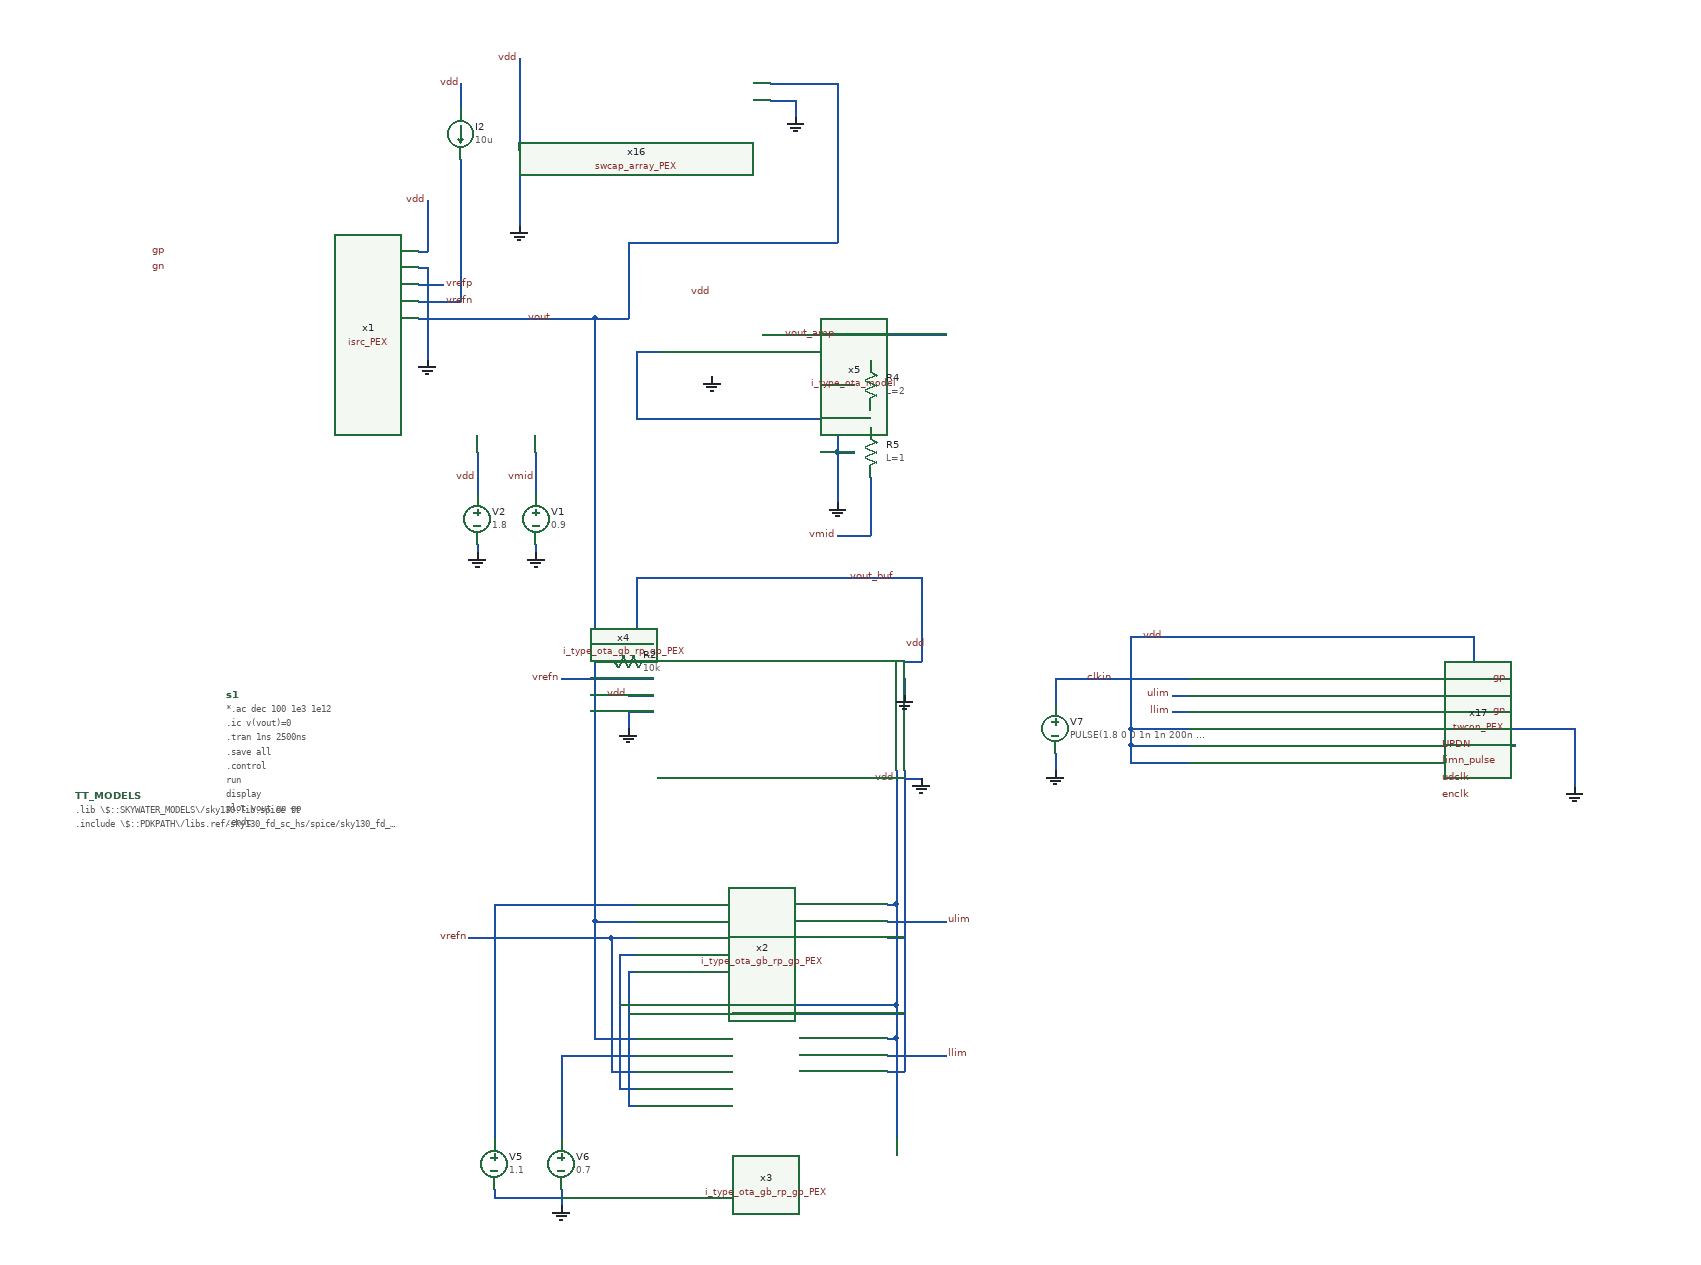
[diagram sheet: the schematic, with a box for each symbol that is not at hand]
v {xschem version=3.1.0 file_version=1.2
}
G {}
K {}
V {}
S {}
E {}
N 440 -10 440 0 {
lab=GND}
N 510 90 510 280 {
lab=vout}
N 470 660 470 700 {
lab=#net1}
N 390 550 390 700 {
lab=#net2}
N 470 760 470 780 {
lab=GND}
N 390 760 390 770 {
lab=GND}
N 390 770 470 770 {
lab=GND}
N 1060 240 1060 260 {
lab=GND}
N 390 -280 460 -280 {
lab=vout}
N 510 -280 510 90 {
lab=vout}
N 460 -280 510 -280 {
lab=vout}
N 440 -120 440 -70 {
lab=vmid}
N 840 -170 840 -150 {
lab=#net3}
N 800 -200 820 -200 {
lab=GND}
N 800 -200 800 -120 {
lab=GND}
N 800 -120 820 -120 {
lab=GND}
N 800 -120 800 -60 {
lab=GND}
N 840 -260 840 -230 {
lab=vout_amp}
N 710 -260 840 -260 {
lab=vout_amp}
N 560 -240 590 -240 {
lab=#net3}
N 560 -160 840 -160 {
lab=#net3}
N 560 -240 560 -160 {
lab=#net3}
N 800 -20 840 -20 {
lab=vmid}
N 840 -90 840 -20 {
lab=vmid}
N 840 -260 930 -260 {
lab=vout_amp}
N 1060 150 1060 180 {
lab=clkin}
N 1060 150 1100 150 {
lab=clkin}
N 750 -540 750 -520 {
lab=GND}
N 720 -540 750 -540 {
lab=GND}
N 720 -560 800 -560 {
lab=vout}
N 800 -560 800 -370 {
lab=vout}
N 550 -370 800 -370 {
lab=vout}
N 550 -370 550 -280 {
lab=vout}
N 420 -590 420 -560 {
lab=vdd}
N 1100 150 1220 150 {
lab=clkin}
N 1200 170 1220 170 {
lab=ulim}
N 1200 190 1220 190 {
lab=llim}
N 1190 100 1560 100 {
lab=vdd}
N 1560 100 1560 160 {
lab=vdd}
N 1560 160 1560 170 {
lab=vdd}
N 1520 170 1560 170 {
lab=vdd}
N 1150 100 1190 100 {
lab=vdd}
N 1150 100 1150 210 {
lab=vdd}
N 1150 210 1220 210 {
lab=vdd}
N 1150 230 1220 230 {
lab=vdd}
N 1150 250 1220 250 {
lab=vdd}
N 1150 230 1150 250 {
lab=vdd}
N 1520 150 1580 150 {
lab=gp}
N 1520 210 1560 210 {
lab=GND}
N 1680 210 1680 280 {
lab=GND}
N 1520 190 1580 190 {
lab=gn}
N 1560 210 1680 210 {
lab=GND}
N 1520 230 1610 230 {
lab=UPDN}
N 1150 210 1150 230 {
lab=vdd}
N 300 -360 310 -360 {
lab=vdd}
N 310 -420 310 -360 {
lab=vdd}
N 310 -340 310 -230 {
lab=GND}
N 300 -340 310 -340 {
lab=GND}
N 300 -280 390 -280 {
lab=vout}
N 350 -560 350 -530 {
lab=vdd}
N 370 -120 370 -70 {
lab=vdd}
N 370 -10 370 0 {
lab=GND}
N 300 -320 330 -320 {
lab=vrefp}
N 300 -300 330 -300 {
lab=vrefn}
N 350 -470 350 -300 {
lab=vrefn}
N 330 -300 350 -300 {
lab=vrefn}
N 860 420 870 420 {
lab=vdd}
N 860 440 930 440 {
lab=ulim}
N 860 460 880 460 {
lab=GND}
N 870 260 870 420 {
lab=vdd}
N 870 420 870 540 {
lab=vdd}
N 880 260 880 540 {
lab=GND}
N 880 270 900 270 {
lab=GND}
N 860 580 870 580 {
lab=vdd}
N 860 600 930 600 {
lab=llim}
N 860 620 880 620 {
lab=GND}
N 870 580 870 700 {
lab=vdd}
N 870 540 870 580 {
lab=vdd}
N 880 540 880 620 {
lab=GND}
N 390 440 390 550 {
lab=#net2}
N 390 420 390 440 {
lab=#net2}
N 390 420 560 420 {
lab=#net2}
N 470 600 470 660 {
lab=#net1}
N 470 600 560 600 {
lab=#net1}
N 540 480 560 480 {
lab=vdd}
N 540 480 540 640 {
lab=vdd}
N 540 640 560 640 {
lab=vdd}
N 550 660 560 660 {
lab=GND}
N 550 500 550 660 {
lab=GND}
N 550 500 560 500 {
lab=GND}
N 540 540 870 540 {
lab=vdd}
N 550 550 880 550 {
lab=GND}
N 530 460 560 460 {
lab=vrefn}
N 530 460 530 620 {
lab=vrefn}
N 530 620 560 620 {
lab=vrefn}
N 360 460 530 460 {
lab=vrefn}
N 510 440 560 440 {
lab=vout}
N 510 440 510 580 {
lab=vout}
N 510 580 560 580 {
lab=vout}
N 510 280 510 440 {
lab=vout}
N 510 -280 550 -280 {
lab=vout}
N 420 -560 420 -480 {
lab=vdd}
N 420 -460 420 -390 {
lab=GND}
N 560 110 580 110 {
lab=vout_buf}
N 560 30 560 110 {
lab=vout_buf}
N 560 30 900 30 {
lab=vout_buf}
N 900 30 900 130 {
lab=vout_buf}
N 890 130 900 130 {
lab=vout_buf}
N 880 130 890 130 {
lab=vout_buf}
N 880 150 880 170 {
lab=GND}
N 550 190 550 210 {
lab=GND}
N 470 150 490 150 {
lab=vrefn}
N 490 150 580 150 {
lab=vrefn}
N 510 130 520 130 {
lab=vout}
N 550 170 580 170 {
lab=vdd}
N 550 190 580 190 {
lab=GND}
C {devices/gnd.sym} 440 0 0 0 {name=l2 lab=GND}
C {devices/vsource.sym} 440 -40 0 0 {name=V1 value=0.9}
C {devices/vsource.sym} 370 -40 0 0 {name=V2 value=1.8}
C {devices/lab_wire.sym} 370 -90 0 0 {name=p1 sig_type=std_logic lab=vdd}
C {devices/lab_wire.sym} 460 -280 0 0 {name=p2 sig_type=std_logic lab=vout}
C {devices/code.sym} -110 290 0 0 {name=TT_MODELS only_toplevel=false
format="tcleval(@value )" value=".lib \\\\$::SKYWATER_MODELS\\\\/sky130.lib.spice tt
.include \\\\$::PDKPATH\\\\/libs.ref/sky130_fd_sc_hs/spice/sky130_fd_sc_hs.spice"}
C {devices/code_shown.sym} 70 170 0 0 {name=s1
only_toplevel=false
value="
*.ac dec 100 1e3 1e12
.ic v(vout)=0
.tran 1ns 2500ns
.save all
.control
run
display
plot vout gn gp
.endc
"}
C {devices/lab_wire.sym} 870 270 0 0 {name=p7 sig_type=std_logic lab=vdd}
C {devices/lab_wire.sym} 930 440 0 1 {name=p8 sig_type=std_logic lab=ulim}
C {devices/vsource.sym} 390 730 0 0 {name=V5 value="1.1"}
C {devices/vsource.sym} 470 730 0 0 {name=V6 value="0.7"}
C {devices/gnd.sym} 470 780 0 0 {name=l7 lab=GND}
C {devices/vsource.sym} 1060 210 0 0 {name=V7 value="PULSE(1.8 0 0 1n 1n 200n 400n)"}
C {devices/gnd.sym} 1060 260 0 0 {name=l8 lab=GND}
C {devices/lab_wire.sym} 440 -90 0 0 {name=p18 sig_type=std_logic lab=vmid}
C {i_type_ota_model.sym} 650 -260 0 0 {name=x5}
C {devices/lab_wire.sym} 650 -310 0 0 {name=p10 sig_type=std_logic lab=vdd}
C {devices/gnd.sym} 650 -210 0 0 {name=l4 lab=GND}
C {sky130_fd_pr/res_xhigh_po_0p35.sym} 840 -200 0 0 {name=R4
L=2
model=res_xhigh_po_0p35
spiceprefix=X
mult=1}
C {sky130_fd_pr/res_xhigh_po_0p35.sym} 840 -120 0 0 {name=R5
L=1
model=res_xhigh_po_0p35
spiceprefix=X
mult=1}
C {devices/gnd.sym} 800 -60 0 0 {name=l6 lab=GND}
C {devices/lab_wire.sym} 800 -20 0 0 {name=p14 sig_type=std_logic lab=vmid}
C {devices/lab_wire.sym} 800 -260 0 0 {name=p19 sig_type=std_logic lab=vout_amp}
C {swcap_array_PEX.sym} 570 -490 0 0 {name=x16}
C {devices/gnd.sym} 750 -520 0 0 {name=l14 lab=GND}
C {devices/gnd.sym} 420 -390 0 0 {name=l15 lab=GND}
C {devices/lab_wire.sym} 420 -590 0 0 {name=p25 sig_type=std_logic lab=vdd}
C {twcon_PEX.sym} 1370 220 0 0 {name=x17}
C {devices/lab_wire.sym} 1200 170 0 0 {name=p26 sig_type=std_logic lab=ulim}
C {devices/lab_wire.sym} 1200 190 0 0 {name=p27 sig_type=std_logic lab=llim}
C {devices/lab_wire.sym} 1190 100 0 0 {name=p28 sig_type=std_logic lab=vdd}
C {devices/gnd.sym} 1680 280 0 0 {name=l16 lab=GND}
C {devices/lab_wire.sym} 1580 150 0 1 {name=p29 sig_type=std_logic lab=gp}
C {devices/lab_wire.sym} 1580 190 0 1 {name=p30 sig_type=std_logic lab=gn}
C {devices/lab_wire.sym} 1520 230 0 1 {name=p11 sig_type=std_logic lab=UPDN}
C {devices/lab_wire.sym} 1520 250 0 1 {name=p12 sig_type=std_logic lab=limn_pulse}
C {devices/lab_wire.sym} 1520 270 0 1 {name=p13 sig_type=std_logic lab=udclk}
C {devices/lab_wire.sym} 1520 290 0 1 {name=p15 sig_type=std_logic lab=enclk}
C {devices/lab_wire.sym} 1130 150 0 0 {name=p16 sig_type=std_logic lab=clkin}
C {isrc_PEX.sym} 150 -310 0 0 {name=x1}
C {devices/lab_wire.sym} 310 -420 0 0 {name=p3 sig_type=std_logic lab=vdd}
C {devices/gnd.sym} 310 -230 0 0 {name=l1 lab=GND}
C {devices/isource.sym} 350 -500 0 0 {name=I2 value=10u}
C {devices/lab_wire.sym} 350 -560 0 0 {name=p4 sig_type=std_logic lab=vdd}
C {devices/gnd.sym} 370 0 0 0 {name=l3 lab=GND}
C {devices/lab_wire.sym} 0 -360 0 0 {name=p5 sig_type=std_logic lab=gp}
C {devices/lab_wire.sym} 0 -340 0 0 {name=p6 sig_type=std_logic lab=gn}
C {devices/lab_wire.sym} 330 -320 0 1 {name=p17 sig_type=std_logic lab=vrefp}
C {devices/lab_wire.sym} 330 -300 0 1 {name=p20 sig_type=std_logic lab=vrefn}
C {i_type_ota_gb_rp_gp_PEX.sym} 710 460 0 0 {name=x2}
C {devices/gnd.sym} 900 270 0 0 {name=l9 lab=GND}
C {i_type_ota_gb_rp_gp_PEX.sym} 710 620 0 0 {name=x3}
C {devices/lab_wire.sym} 930 600 0 1 {name=p21 sig_type=std_logic lab=llim}
C {devices/lab_wire.sym} 360 460 0 0 {name=p9 sig_type=std_logic lab=vrefn}
C {i_type_ota_gb_rp_gp_PEX.sym} 730 150 0 0 {name=x4}
C {devices/lab_wire.sym} 880 110 0 1 {name=p22 sig_type=std_logic lab=vdd}
C {devices/gnd.sym} 880 170 0 0 {name=l5 lab=GND}
C {devices/lab_wire.sym} 470 150 0 0 {name=p23 sig_type=std_logic lab=vrefn}
C {devices/gnd.sym} 550 210 0 0 {name=l10 lab=GND}
C {devices/lab_wire.sym} 550 170 0 0 {name=p24 sig_type=std_logic lab=vdd}
C {devices/lab_wire.sym} 870 30 0 0 {name=p31 sig_type=std_logic lab=vout_buf}
C {devices/res.sym} 550 130 1 0 {name=R2
value=10k
footprint=1206
device=resistor
m=1}
